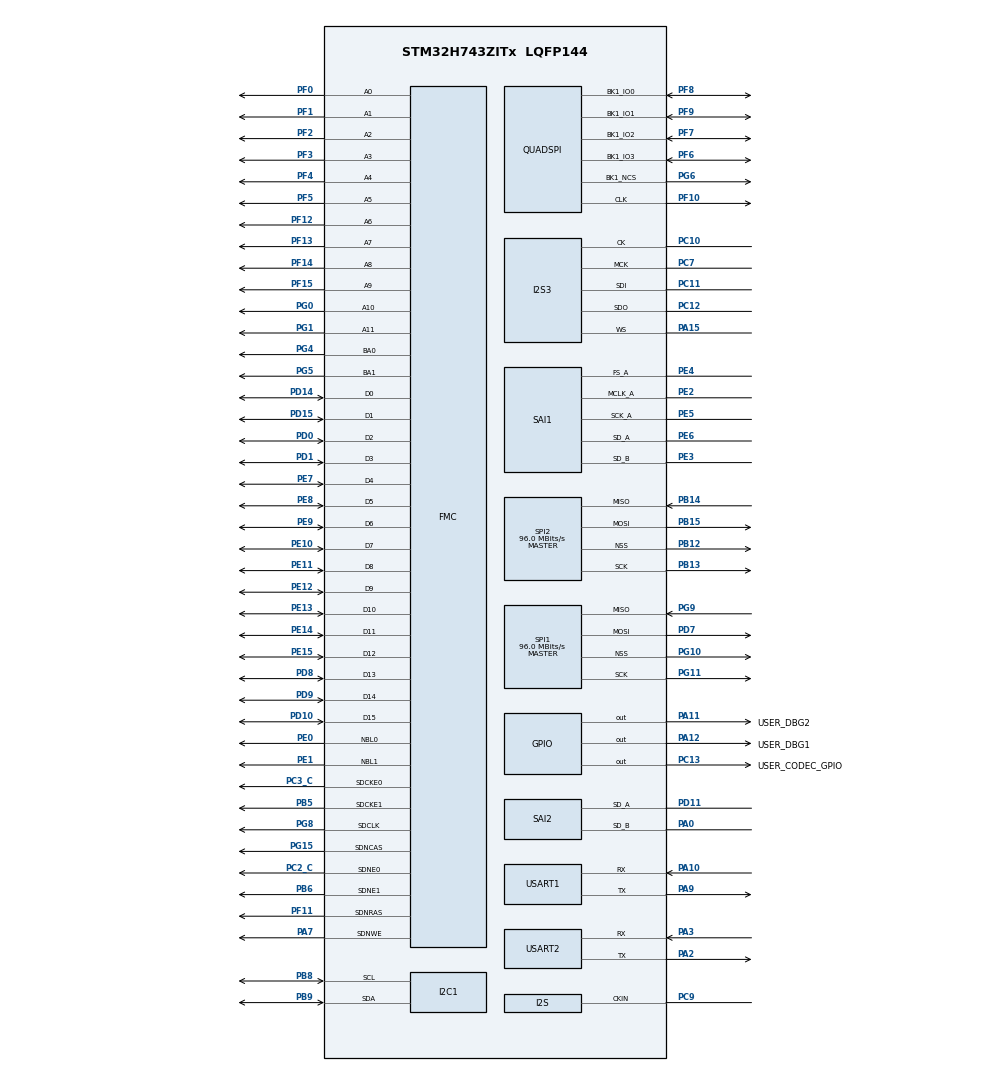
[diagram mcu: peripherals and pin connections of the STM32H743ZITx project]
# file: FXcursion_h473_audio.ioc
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CORTEX_M7.AccessPermission-Cortex_Memory_Protection_Unit_Region0_Settings=MPU_REGION_FULL_ACCESS
CORTEX_M7.AccessPermission-Cortex_Memory_Protection_Unit_Region1_Settings=MPU_REGION_FULL_ACCESS
CORTEX_M7.AccessPermission-Cortex_Memory_Protection_Unit_Region2_Settings=MPU_REGION_FULL_ACCESS
CORTEX_M7.BaseAddress-Cortex_Memory_Protection_Unit_Region0_Settings=0x30000000
CORTEX_M7.BaseAddress-Cortex_Memory_Protection_Unit_Region1_Settings=0xC0000000
CORTEX_M7.BaseAddress-Cortex_Memory_Protection_Unit_Region2_Settings=0x38000000
CORTEX_M7.CPU_DCache=Enabled
CORTEX_M7.CPU_ICache=Enabled
CORTEX_M7.DisableExec-Cortex_Memory_Protection_Unit_Region0_Settings=MPU_INSTRUCTION_ACCESS_DISABLE
CORTEX_M7.DisableExec-Cortex_Memory_Protection_Unit_Region2_Settings=MPU_INSTRUCTION_ACCESS_DISABLE
CORTEX_M7.Enable-Cortex_Memory_Protection_Unit_Region0_Settings=MPU_REGION_ENABLE
CORTEX_M7.Enable-Cortex_Memory_Protection_Unit_Region1_Settings=MPU_REGION_ENABLE
CORTEX_M7.Enable-Cortex_Memory_Protection_Unit_Region2_Settings=MPU_REGION_ENABLE
CORTEX_M7.IsBufferable-Cortex_Memory_Protection_Unit_Region0_Settings=MPU_ACCESS_BUFFERABLE
CORTEX_M7.IsBufferable-Cortex_Memory_Protection_Unit_Region2_Settings=MPU_ACCESS_BUFFERABLE
CORTEX_M7.IsCacheable-Cortex_Memory_Protection_Unit_Region1_Settings=MPU_ACCESS_CACHEABLE
CORTEX_M7.IsShareable-Cortex_Memory_Protection_Unit_Region0_Settings=MPU_ACCESS_SHAREABLE
CORTEX_M7.IsShareable-Cortex_Memory_Protection_Unit_Region2_Settings=MPU_ACCESS_SHAREABLE
CORTEX_M7.MPU_Control=MPU_PRIVILEGED_DEFAULT
CORTEX_M7.Size-Cortex_Memory_Protection_Unit_Region0_Settings=MPU_REGION_SIZE_256KB
CORTEX_M7.Size-Cortex_Memory_Protection_Unit_Region1_Settings=MPU_REGION_SIZE_512MB
CORTEX_M7.Size-Cortex_Memory_Protection_Unit_Region2_Settings=MPU_REGION_SIZE_64KB
Dma.Request0=SAI1_A
Dma.Request1=SAI1_B
Dma.Request2=USART2_RX
Dma.Request3=USART2_TX
Dma.Request4=SPI1_RX
Dma.Request5=SPI1_TX
Dma.SAI1_A.0.Direction=DMA_PERIPH_TO_MEMORY
Dma.SAI1_A.0.EventEnable=DISABLE
Dma.SAI1_A.0.FIFOMode=DMA_FIFOMODE_DISABLE
Dma.SAI1_A.0.Instance=DMA1_Stream0
Dma.SAI1_A.0.MemDataAlignment=DMA_MDATAALIGN_WORD
Dma.SAI1_A.0.MemInc=DMA_MINC_ENABLE
Dma.SAI1_A.0.Mode=DMA_CIRCULAR
Dma.SAI1_A.0.PeriphDataAlignment=DMA_PDATAALIGN_WORD
Dma.SAI1_A.0.PeriphInc=DMA_PINC_DISABLE
Dma.SAI1_A.0.Polarity=HAL_DMAMUX_REQ_GEN_RISING
Dma.SAI1_A.0.Priority=DMA_PRIORITY_HIGH
Dma.SAI1_A.0.RequestNumber=1
Dma.SAI1_A.0.SignalID=NONE
Dma.SAI1_A.0.SyncEnable=DISABLE
Dma.SAI1_A.0.SyncPolarity=HAL_DMAMUX_SYNC_NO_EVENT
Dma.SAI1_A.0.SyncRequestNumber=1
Dma.SAI1_A.0.SyncSignalID=NONE
Dma.SAI1_B.1.Direction=DMA_MEMORY_TO_PERIPH
Dma.SAI1_B.1.EventEnable=DISABLE
Dma.SAI1_B.1.FIFOMode=DMA_FIFOMODE_DISABLE
Dma.SAI1_B.1.Instance=DMA1_Stream1
Dma.SAI1_B.1.MemDataAlignment=DMA_MDATAALIGN_WORD
Dma.SAI1_B.1.MemInc=DMA_MINC_ENABLE
Dma.SAI1_B.1.Mode=DMA_CIRCULAR
Dma.SAI1_B.1.PeriphDataAlignment=DMA_PDATAALIGN_WORD
Dma.SAI1_B.1.PeriphInc=DMA_PINC_DISABLE
Dma.SAI1_B.1.Polarity=HAL_DMAMUX_REQ_GEN_RISING
Dma.SAI1_B.1.Priority=DMA_PRIORITY_MEDIUM
Dma.SAI1_B.1.RequestNumber=1
Dma.SAI1_B.1.SignalID=NONE
Dma.SAI1_B.1.SyncEnable=DISABLE
Dma.SAI1_B.1.SyncPolarity=HAL_DMAMUX_SYNC_NO_EVENT
Dma.SAI1_B.1.SyncRequestNumber=1
Dma.SAI1_B.1.SyncSignalID=NONE
Dma.SPI1_RX.4.Direction=DMA_PERIPH_TO_MEMORY
Dma.SPI1_RX.4.EventEnable=DISABLE
Dma.SPI1_RX.4.FIFOMode=DMA_FIFOMODE_DISABLE
Dma.SPI1_RX.4.Instance=DMA1_Stream4
Dma.SPI1_RX.4.MemDataAlignment=DMA_MDATAALIGN_WORD
Dma.SPI1_RX.4.MemInc=DMA_MINC_ENABLE
Dma.SPI1_RX.4.Mode=DMA_NORMAL
Dma.SPI1_RX.4.PeriphDataAlignment=DMA_PDATAALIGN_WORD
Dma.SPI1_RX.4.PeriphInc=DMA_PINC_DISABLE
Dma.SPI1_RX.4.Polarity=HAL_DMAMUX_REQ_GEN_RISING
Dma.SPI1_RX.4.Priority=DMA_PRIORITY_LOW
Dma.SPI1_RX.4.RequestNumber=1
Dma.SPI1_RX.4.SignalID=NONE
Dma.SPI1_RX.4.SyncEnable=DISABLE
Dma.SPI1_RX.4.SyncPolarity=HAL_DMAMUX_SYNC_NO_EVENT
Dma.SPI1_RX.4.SyncRequestNumber=1
Dma.SPI1_RX.4.SyncSignalID=NONE
Dma.SPI1_TX.5.Direction=DMA_MEMORY_TO_PERIPH
Dma.SPI1_TX.5.EventEnable=DISABLE
Dma.SPI1_TX.5.FIFOMode=DMA_FIFOMODE_DISABLE
Dma.SPI1_TX.5.Instance=DMA1_Stream5
Dma.SPI1_TX.5.MemDataAlignment=DMA_MDATAALIGN_WORD
Dma.SPI1_TX.5.MemInc=DMA_MINC_ENABLE
Dma.SPI1_TX.5.Mode=DMA_NORMAL
Dma.SPI1_TX.5.PeriphDataAlignment=DMA_PDATAALIGN_WORD
Dma.SPI1_TX.5.PeriphInc=DMA_PINC_DISABLE
Dma.SPI1_TX.5.Polarity=HAL_DMAMUX_REQ_GEN_RISING
Dma.SPI1_TX.5.Priority=DMA_PRIORITY_LOW
Dma.SPI1_TX.5.RequestNumber=1
Dma.SPI1_TX.5.SignalID=NONE
Dma.SPI1_TX.5.SyncEnable=DISABLE
Dma.SPI1_TX.5.SyncPolarity=HAL_DMAMUX_SYNC_NO_EVENT
Dma.SPI1_TX.5.SyncRequestNumber=1
Dma.SPI1_TX.5.SyncSignalID=NONE
Dma.USART2_RX.2.Direction=DMA_PERIPH_TO_MEMORY
Dma.USART2_RX.2.EventEnable=DISABLE
Dma.USART2_RX.2.FIFOMode=DMA_FIFOMODE_DISABLE
Dma.USART2_RX.2.Instance=DMA1_Stream2
Dma.USART2_RX.2.MemDataAlignment=DMA_MDATAALIGN_BYTE
Dma.USART2_RX.2.MemInc=DMA_MINC_ENABLE
Dma.USART2_RX.2.Mode=DMA_CIRCULAR
Dma.USART2_RX.2.PeriphDataAlignment=DMA_PDATAALIGN_BYTE
Dma.USART2_RX.2.PeriphInc=DMA_PINC_DISABLE
Dma.USART2_RX.2.Polarity=HAL_DMAMUX_REQ_GEN_RISING
Dma.USART2_RX.2.Priority=DMA_PRIORITY_LOW
Dma.USART2_RX.2.RequestNumber=1
Dma.USART2_RX.2.SignalID=NONE
Dma.USART2_RX.2.SyncEnable=DISABLE
Dma.USART2_RX.2.SyncPolarity=HAL_DMAMUX_SYNC_NO_EVENT
Dma.USART2_RX.2.SyncRequestNumber=1
Dma.USART2_RX.2.SyncSignalID=NONE
Dma.USART2_TX.3.Direction=DMA_MEMORY_TO_PERIPH
Dma.USART2_TX.3.EventEnable=DISABLE
Dma.USART2_TX.3.FIFOMode=DMA_FIFOMODE_DISABLE
Dma.USART2_TX.3.Instance=DMA1_Stream3
Dma.USART2_TX.3.MemDataAlignment=DMA_MDATAALIGN_BYTE
Dma.USART2_TX.3.MemInc=DMA_MINC_ENABLE
Dma.USART2_TX.3.Mode=DMA_NORMAL
Dma.USART2_TX.3.PeriphDataAlignment=DMA_PDATAALIGN_BYTE
Dma.USART2_TX.3.PeriphInc=DMA_PINC_DISABLE
Dma.USART2_TX.3.Polarity=HAL_DMAMUX_REQ_GEN_RISING
Dma.USART2_TX.3.Priority=DMA_PRIORITY_LOW
Dma.USART2_TX.3.RequestNumber=1
Dma.USART2_TX.3.SignalID=NONE
Dma.USART2_TX.3.SyncEnable=DISABLE
Dma.USART2_TX.3.SyncPolarity=HAL_DMAMUX_SYNC_NO_EVENT
Dma.USART2_TX.3.SyncRequestNumber=1
Dma.USART2_TX.3.SyncSignalID=NONE
FMC.CASLatency1=FMC_SDRAM_CAS_LATENCY_2
FMC.CASLatency2=FMC_SDRAM_CAS_LATENCY_2
FMC.ColumnBitsNumber1=FMC_SDRAM_COLUMN_BITS_NUM_9
FMC.ColumnBitsNumber2=FMC_SDRAM_COLUMN_BITS_NUM_9
FMC.LoadToActiveDelay1=6
FMC.RCDDelay1=6
FMC.RPDelay1=6
FMC.RPDelay2=6
FMC.ReadBurst1=FMC_SDRAM_RBURST_ENABLE
FMC.ReadBurst2=FMC_SDRAM_RBURST_ENABLE
FMC.SDClockPeriod1=FMC_SDRAM_CLOCK_PERIOD_2
FMC.SDClockPeriod2=FMC_SDRAM_CLOCK_PERIOD_2
FMC.SelfRefreshTime1=11
FMC.WriteRecoveryTime1=6
FMC.WriteRecoveryTime2=6
I2C1.Timing=0x307075B1
I2S3.ErrorAudioFreq=0.0 %
I2S3.Instance=SPI$Index
I2S3.RealAudioFreq=48.0 KHz
Mcu.Family=STM32H7
Mcu.Name=STM32H743ZITx
Mcu.Package=LQFP144
Mcu.UserConstants=MPU_D3_NONCACHABLE_0x38__,1;FAFA,0xFAFA;CODEC_0_SAI,SAI1;CODEC_1_SAI,SAI2;CODEC_HP_I2S,SPI3;CODEC_CTRL_I2C,I2C1;SAMPLES_SPI,SPI1;FILTER_CTRL_SPI,SPI2;PSRAM_QSPI,QUADSPI;CTRL_UART,USART1;DEBUG_UART,USART2
Mdma.MDMA_Channel0.Request0=QUADSPI_FIFO_TH
Mdma.MDMA_Channel0.RequestsNb=1
Mdma.MDMA_Channel0.QUADSPI_FIFO_TH.0.BlockCount=0
Mdma.MDMA_Channel0.QUADSPI_FIFO_TH.0.BlockDataLength=0
Mdma.MDMA_Channel0.QUADSPI_FIFO_TH.0.BufferTransferLength=4
Mdma.MDMA_Channel0.QUADSPI_FIFO_TH.0.CircularMode=MDMA_LINEAR_LIST
Mdma.MDMA_Channel0.QUADSPI_FIFO_TH.0.DataAlignment=MDMA_DATAALIGN_PACKENABLE
Mdma.MDMA_Channel0.QUADSPI_FIFO_TH.0.DestBlockAddressOffset=0
Mdma.MDMA_Channel0.QUADSPI_FIFO_TH.0.DestBurst=MDMA_DEST_BURST_SINGLE
Mdma.MDMA_Channel0.QUADSPI_FIFO_TH.0.DestDataSize=MDMA_DEST_DATASIZE_BYTE
Mdma.MDMA_Channel0.QUADSPI_FIFO_TH.0.DestinationInc=MDMA_DEST_INC_BYTE
Mdma.MDMA_Channel0.QUADSPI_FIFO_TH.0.DstAddress=DST_ADDRESS
Mdma.MDMA_Channel0.QUADSPI_FIFO_TH.0.Endianness=MDMA_LITTLE_ENDIANNESS_PRESERVE
Mdma.MDMA_Channel0.QUADSPI_FIFO_TH.0.Instance=MDMA_Channel0
Mdma.MDMA_Channel0.QUADSPI_FIFO_TH.0.MaskAddress=0
Mdma.MDMA_Channel0.QUADSPI_FIFO_TH.0.MaskData=0
Mdma.MDMA_Channel0.QUADSPI_FIFO_TH.0.Priority=MDMA_PRIORITY_HIGH
Mdma.MDMA_Channel0.QUADSPI_FIFO_TH.0.Rank=First
Mdma.MDMA_Channel0.QUADSPI_FIFO_TH.0.SourceBlockAddressOffset=0
Mdma.MDMA_Channel0.QUADSPI_FIFO_TH.0.SourceBurst=MDMA_SOURCE_BURST_SINGLE
Mdma.MDMA_Channel0.QUADSPI_FIFO_TH.0.SourceDataSize=MDMA_SRC_DATASIZE_BYTE
Mdma.MDMA_Channel0.QUADSPI_FIFO_TH.0.SourceInc=MDMA_SRC_INC_BYTE
Mdma.MDMA_Channel0.QUADSPI_FIFO_TH.0.SrcAddress=SRC_ADDRESS
Mdma.MDMA_Channel0.QUADSPI_FIFO_TH.0.TransferTriggerMode=MDMA_BUFFER_TRANSFER
Mdma.RequestSet0=MDMA_Channel0
Mdma.RequestSetsNb=1
NVIC.DMA1_Stream0_IRQn=true\:0\:0\:false\:false\:true\:false\:true\:true
NVIC.DMA1_Stream1_IRQn=true\:0\:0\:false\:false\:true\:false\:true\:true
NVIC.DMA1_Stream2_IRQn=true\:0\:0\:false\:false\:true\:false\:true\:true
NVIC.DMA1_Stream3_IRQn=true\:0\:0\:false\:false\:true\:false\:true\:true
NVIC.DMA1_Stream4_IRQn=true\:0\:0\:false\:false\:true\:false\:true\:true
NVIC.DMA1_Stream5_IRQn=true\:0\:0\:false\:false\:true\:false\:true\:true
NVIC.MDMA_IRQn=true\:0\:0\:false\:false\:true\:false\:true\:true
NVIC.PriorityGroup=NVIC_PRIORITYGROUP_4
NVIC.SAI1_IRQn=true\:0\:0\:false\:false\:true\:true\:true\:true
NVIC.SPI1_IRQn=true\:0\:0\:false\:false\:true\:false\:true\:true
NVIC.USART2_IRQn=true\:0\:0\:false\:false\:true\:true\:true\:true
PA0.Mode=SAI_B_SyncSlave
PA0.Signal=SAI2_SD_B
PA10.Mode=Asynchronous
PA10.Signal=USART1_RX
PA11.GPIO_Label=USER_DBG2
PA11.Signal=GPIO_Output
PA12.GPIO_Label=USER_DBG1
PA12.GPIO_Speed=GPIO_SPEED_FREQ_VERY_HIGH
PA12.Signal=GPIO_Output
PA13\ (JTMS/SWDIO).Mode=Serial_Wire
PA13\ (JTMS/SWDIO).Signal=DEBUG_JTMS-SWDIO
PA14\ (JTCK/SWCLK).Mode=Serial_Wire
PA14\ (JTCK/SWCLK).Signal=DEBUG_JTCK-SWCLK
PA15\ (JTDI).Mode=Full_Duplex_Master
PA15\ (JTDI).Signal=I2S3_WS
PA2.Mode=Asynchronous
PA2.Signal=USART2_TX
PA3.Mode=Asynchronous
PA3.Signal=USART2_RX
PA7.Signal=FMC_SDNWE
PA9.Mode=Asynchronous
PA9.Signal=USART1_TX
PB12.Mode=NSS_Signal_Hard_Output
PB12.Signal=SPI2_NSS
PB13.Mode=Full_Duplex_Master
PB13.Signal=SPI2_SCK
PB14.Mode=Full_Duplex_Master
PB14.Signal=SPI2_MISO
PB15.Mode=Full_Duplex_Master
PB15.Signal=SPI2_MOSI
PB5.Mode=SdramChipSelect2_2
PB5.Signal=FMC_SDCKE1
PB6.Mode=SdramChipSelect2_2
PB6.Signal=FMC_SDNE1
PB8.Mode=I2C
PB8.Signal=I2C1_SCL
PB9.Mode=I2C
PB9.Signal=I2C1_SDA
PC10.Mode=Full_Duplex_Master
PC10.Signal=I2S3_CK
PC11.Mode=Full_Duplex_Master
PC11.Signal=I2S3_SDI
PC12.Mode=Full_Duplex_Master
PC12.Signal=I2S3_SDO
PC13.GPIO_Label=USER_CODEC_GPIO
PC13.Signal=GPIO_Output
PC2_C.Mode=SdramChipSelect1_1
PC2_C.Signal=FMC_SDNE0
PC3_C.Mode=SdramChipSelect1_1
PC3_C.Signal=FMC_SDCKE0
PC7.Mode=Master_Clock_Activated
PC7.Signal=I2S3_MCK
PC9.Mode=Audio_ClockIn
PC9.Signal=I2S_CKIN
PD0.Signal=FMC_D2_DA2
PD1.Signal=FMC_D3_DA3
PD10.Signal=FMC_D15_DA15
PD11.Mode=SAI_A_SyncSlave
PD11.Signal=SAI2_SD_A
PD12.Signal=SAI2_FS_A
PD13.Signal=SAI2_SCK_A
PD14.Signal=FMC_D0_DA0
PD15.Signal=FMC_D1_DA1
PD7.GPIO_Speed=GPIO_SPEED_FREQ_VERY_HIGH
PD7.Mode=Full_Duplex_Master
PD7.Signal=SPI1_MOSI
PD8.Signal=FMC_D13_DA13
PD9.Signal=FMC_D14_DA14
PE0.Signal=FMC_NBL0
PE1.Signal=FMC_NBL1
PE10.Signal=FMC_D7_DA7
PE11.Signal=FMC_D8_DA8
PE12.Signal=FMC_D9_DA9
PE13.Signal=FMC_D10_DA10
PE14.Signal=FMC_D11_DA11
PE15.Signal=FMC_D12_DA12
PE2.Mode=SAI_A_MasterWithClock
PE2.Signal=SAI1_MCLK_A
PE3.GPIO_Speed=GPIO_SPEED_FREQ_VERY_HIGH
PE3.Mode=SAI_B_SyncSlave
PE3.Signal=SAI1_SD_B
PE4.GPIO_Speed=GPIO_SPEED_FREQ_VERY_HIGH
PE4.Mode=SAI_A_MasterWithClock
PE4.Signal=SAI1_FS_A
PE5.GPIO_Speed=GPIO_SPEED_FREQ_VERY_HIGH
PE5.Mode=SAI_A_MasterWithClock
PE5.Signal=SAI1_SCK_A
PE6.GPIO_Speed=GPIO_SPEED_FREQ_VERY_HIGH
PE6.Mode=SAI_A_MasterWithClock
PE6.Signal=SAI1_SD_A
PE7.Signal=FMC_D4_DA4
PE8.Signal=FMC_D5_DA5
PE9.Signal=FMC_D6_DA6
PF0.Signal=FMC_A0
PF1.Signal=FMC_A1
PF10.Mode=Single Bank 1
PF10.Signal=QUADSPI_CLK
PF11.Signal=FMC_SDNRAS
PF12.Signal=FMC_A6
PF13.Signal=FMC_A7
PF14.Signal=FMC_A8
PF15.Signal=FMC_A9
PF2.Signal=FMC_A2
PF3.Signal=FMC_A3
PF4.Signal=FMC_A4
PF5.Signal=FMC_A5
PF6.Mode=Single Bank 1
PF6.Signal=QUADSPI_BK1_IO3
PF7.Mode=Single Bank 1
PF7.Signal=QUADSPI_BK1_IO2
PF8.Mode=Single Bank 1
PF8.Signal=QUADSPI_BK1_IO0
PF9.Mode=Single Bank 1
PF9.Signal=QUADSPI_BK1_IO1
PG0.Signal=FMC_A10
PG1.Signal=FMC_A11
PG10.GPIO_Speed=GPIO_SPEED_FREQ_VERY_HIGH
PG10.Mode=NSS_Signal_Hard_Output
PG10.Signal=SPI1_NSS
PG11.GPIO_Speed=GPIO_SPEED_FREQ_VERY_HIGH
PG11.Mode=Full_Duplex_Master
PG11.Signal=SPI1_SCK
PG15.Signal=FMC_SDNCAS
PG4.Signal=FMC_A14_BA0
PG5.Signal=FMC_A15_BA1
PG6.Mode=Single Bank 1
PG6.Signal=QUADSPI_BK1_NCS
PG8.Signal=FMC_SDCLK
PG9.GPIO_Speed=GPIO_SPEED_FREQ_VERY_HIGH
PG9.Mode=Full_Duplex_Master
PG9.Signal=SPI1_MISO
ProjectManager.HeapSize=0x200
ProjectManager.StackSize=0x400
ProjectManager.TargetToolchain=STM32CubeIDE
RCC.ADCFreq_Value=12288000
RCC.APB1Freq_Value=120000000
RCC.APB2Freq_Value=120000000
RCC.APB3Freq_Value=120000000
RCC.APB4Freq_Value=120000000
RCC.CortexFreq_Value=480000000
RCC.D1PPRE=RCC_APB3_DIV2
RCC.D2PPRE1=RCC_APB1_DIV2
RCC.D2PPRE2=RCC_APB2_DIV2
RCC.D3PPRE=RCC_APB4_DIV2
RCC.DIVM1=2
RCC.DIVM2=10
RCC.DIVM3=4
RCC.DIVN1=120
RCC.DIVN2=192
RCC.DIVN3=96
RCC.DIVP2=25
RCC.DIVQ3=8
RCC.DIVR3=4
RCC.HCLKFreq_Value=240000000
RCC.HPRE=RCC_HCLK_DIV2
RCC.HSIDiv=RCC_PLLSAIDIVR_4
RCC.PLL2FRACN=0
RCC.PLL3FRACN=0
RCC.PLLFRACN=0
RCC.SAI1CLockSelection=RCC_SAI1CLKSOURCE_PIN
RCC.SAI23CLockSelection=RCC_SAI23CLKSOURCE_PIN
RCC.SAI4ACLockSelection=RCC_SAI4ACLKSOURCE_PLL2
RCC.SAI4BCLockSelection=RCC_SAI4BCLKSOURCE_PLL2
RCC.SPI123CLockSelection=RCC_SPI123CLKSOURCE_PIN
RCC.SYSCLKFreq_VALUE=480000000
RCC.SYSCLKSource=RCC_SYSCLKSOURCE_PLLCLK
RCC.USBFreq_Value=480000000
SAI1.AudioMode-SAI_B_SyncSlave=SAI_MODESLAVE_TX
SAI1.BasicDataSize-SAI_B_SyncSlave=SAI_PROTOCOL_DATASIZE_24BIT
SAI1.BasicDataSize-SAI_A_MasterWithClock=SAI_PROTOCOL_DATASIZE_24BIT
SAI1.AudioMode-SAI_A_MasterWithClock=SAI_MODEMASTER_RX
SAI1.AudioFrequency-SAI_A_MasterWithClock=SAI_AUDIO_FREQUENCY_48K
SAI1.ErrorAudioFreq-SAI_A_MasterWithClock=-75.0 %
SAI1.InitProtocol-SAI_A_MasterWithClock=Enable
SAI1.InitProtocol-SAI_B_SyncSlave=Enable
SAI1.Instance-SAI_A_MasterWithClock=SAI$Index_Block_A
SAI1.Instance-SAI_B_SyncSlave=SAI$Index_Block_B
SAI1.MClockEnable-SAI_A_MasterWithClock=SAI_MASTERCLOCK_ENABLE
SAI1.RealAudioFreq-SAI_A_MasterWithClock=48.0 KHz
SAI1.SynchroExt=SAI_SYNCEXT_OUTBLOCKA_ENABLE
SAI1.VirtualMode-SAI_A_MasterWithClock=VM_MASTER
SAI1.VirtualMode-SAI_B_SyncSlave=VM_SLAVE
SAI1.VirtualProtocol-SAI_A_BASIC=VM_BASIC_PROTOCOL
SAI1.VirtualProtocol-SAI_B_BASIC=VM_BASIC_PROTOCOL
SAI2.Instance-SAI_A_SyncSlave=SAI$Index_Block_A
SAI2.Instance-SAI_B_SyncSlave=SAI$Index_Block_B
SAI2.VirtualMode-SAI_A_SyncSlave=VM_SLAVE
SAI2.VirtualMode-SAI_B_SyncSlave=VM_SLAVE
SH.FMC_A0.0=FMC_A0,12b-sda2
SH.FMC_A0.1=FMC_A0,12b-sda1
SH.FMC_A1.0=FMC_A1,12b-sda2
SH.FMC_A1.1=FMC_A1,12b-sda1
SH.FMC_A10.0=FMC_A10,12b-sda2
SH.FMC_A10.1=FMC_A10,12b-sda1
SH.FMC_A11.0=FMC_A11,12b-sda2
SH.FMC_A11.1=FMC_A11,12b-sda1
SH.FMC_A14_BA0.0=FMC_BA0,FourSdramBanks1
SH.FMC_A14_BA0.1=FMC_BA0,FourSdramBanks2
SH.FMC_A15_BA1.0=FMC_BA1,FourSdramBanks1
SH.FMC_A15_BA1.1=FMC_BA1,FourSdramBanks2
SH.FMC_A2.0=FMC_A2,12b-sda2
SH.FMC_A2.1=FMC_A2,12b-sda1
SH.FMC_A3.0=FMC_A3,12b-sda2
SH.FMC_A3.1=FMC_A3,12b-sda1
SH.FMC_A4.0=FMC_A4,12b-sda2
SH.FMC_A4.1=FMC_A4,12b-sda1
SH.FMC_A5.0=FMC_A5,12b-sda2
SH.FMC_A5.1=FMC_A5,12b-sda1
SH.FMC_A6.0=FMC_A6,12b-sda2
SH.FMC_A6.1=FMC_A6,12b-sda1
SH.FMC_A7.0=FMC_A7,12b-sda2
SH.FMC_A7.1=FMC_A7,12b-sda1
SH.FMC_A8.0=FMC_A8,12b-sda2
SH.FMC_A8.1=FMC_A8,12b-sda1
SH.FMC_A9.0=FMC_A9,12b-sda2
SH.FMC_A9.1=FMC_A9,12b-sda1
SH.FMC_D0_DA0.0=FMC_D0,sd-16b-d1
SH.FMC_D0_DA0.1=FMC_D0,sd-16b-d2
SH.FMC_D10_DA10.0=FMC_D10,sd-16b-d1
SH.FMC_D10_DA10.1=FMC_D10,sd-16b-d2
SH.FMC_D11_DA11.0=FMC_D11,sd-16b-d1
SH.FMC_D11_DA11.1=FMC_D11,sd-16b-d2
SH.FMC_D12_DA12.0=FMC_D12,sd-16b-d1
SH.FMC_D12_DA12.1=FMC_D12,sd-16b-d2
SH.FMC_D13_DA13.0=FMC_D13,sd-16b-d1
SH.FMC_D13_DA13.1=FMC_D13,sd-16b-d2
SH.FMC_D14_DA14.0=FMC_D14,sd-16b-d1
SH.FMC_D14_DA14.1=FMC_D14,sd-16b-d2
SH.FMC_D15_DA15.0=FMC_D15,sd-16b-d1
SH.FMC_D15_DA15.1=FMC_D15,sd-16b-d2
SH.FMC_D1_DA1.0=FMC_D1,sd-16b-d1
SH.FMC_D1_DA1.1=FMC_D1,sd-16b-d2
SH.FMC_D2_DA2.0=FMC_D2,sd-16b-d1
SH.FMC_D2_DA2.1=FMC_D2,sd-16b-d2
SH.FMC_D3_DA3.0=FMC_D3,sd-16b-d1
SH.FMC_D3_DA3.1=FMC_D3,sd-16b-d2
SH.FMC_D4_DA4.0=FMC_D4,sd-16b-d1
SH.FMC_D4_DA4.1=FMC_D4,sd-16b-d2
SH.FMC_D5_DA5.0=FMC_D5,sd-16b-d1
SH.FMC_D5_DA5.1=FMC_D5,sd-16b-d2
SH.FMC_D6_DA6.0=FMC_D6,sd-16b-d1
SH.FMC_D6_DA6.1=FMC_D6,sd-16b-d2
SH.FMC_D7_DA7.0=FMC_D7,sd-16b-d1
SH.FMC_D7_DA7.1=FMC_D7,sd-16b-d2
SH.FMC_D8_DA8.0=FMC_D8,sd-16b-d1
SH.FMC_D8_DA8.1=FMC_D8,sd-16b-d2
SH.FMC_D9_DA9.0=FMC_D9,sd-16b-d1
SH.FMC_D9_DA9.1=FMC_D9,sd-16b-d2
SH.FMC_NBL0.0=FMC_NBL0,Sd2ByteEnable1
SH.FMC_NBL0.1=FMC_NBL0,Sd2ByteEnable2
SH.FMC_NBL1.0=FMC_NBL1,Sd2ByteEnable1
SH.FMC_NBL1.1=FMC_NBL1,Sd2ByteEnable2
SH.FMC_SDCLK.0=FMC_SDCLK,12b-sda2
SH.FMC_SDCLK.1=FMC_SDCLK,12b-sda1
SH.FMC_SDNCAS.0=FMC_SDNCAS,12b-sda2
SH.FMC_SDNCAS.1=FMC_SDNCAS,12b-sda1
SH.FMC_SDNRAS.0=FMC_SDNRAS,12b-sda2
SH.FMC_SDNRAS.1=FMC_SDNRAS,12b-sda1
SH.FMC_SDNWE.0=FMC_SDNWE,12b-sda2
SH.FMC_SDNWE.1=FMC_SDNWE,12b-sda1
SPI1.BaudRatePrescaler=SPI_BAUDRATEPRESCALER_2
SPI1.CalculateBaudRate=96.0 MBits/s
SPI1.DataSize=SPI_DATASIZE_32BIT
SPI1.Direction=SPI_DIRECTION_2LINES
SPI1.Mode=SPI_MODE_MASTER
SPI1.VirtualNSS=VM_NSSHARD
SPI1.VirtualType=VM_MASTER
SPI2.CalculateBaudRate=96.0 MBits/s
SPI2.Direction=SPI_DIRECTION_2LINES
SPI2.Mode=SPI_MODE_MASTER
SPI2.VirtualNSS=VM_NSSHARD
SPI2.VirtualType=VM_MASTER
USART1.VirtualMode-Asynchronous=VM_ASYNC
USART2.RXFIFOThreshold=RXFIFO_THRESHOLD_1EIGHTHFULL
USART2.TXFIFOThreshold=TXFIFO_THRESHOLD_1EIGHTHFULL
USART2.VirtualMode-Asynchronous=VM_ASYNC
VP_SAI1_VP_$IpInstance_SAIA_SAI_BASIC.Mode=SAI_A_BASIC
VP_SAI1_VP_$IpInstance_SAIB_SAI_BASIC.Mode=SAI_B_BASIC
VP_SAI1_VP_$IpInstance_SYNCHRO_EXTERNAL.Mode=SynchroExternal
board=custom
Dma.SAI2_A.6.Direction=DMA_PERIPH_TO_MEMORY
Dma.SAI2_A.6.EventEnable=DISABLE
Dma.SAI2_A.6.FIFOMode=DMA_FIFOMODE_DISABLE
Dma.SAI2_A.6.Instance=DMA1_Stream6
Dma.SAI2_A.6.MemDataAlignment=DMA_MDATAALIGN_WORD
Dma.SAI2_A.6.MemInc=DMA_MINC_ENABLE
Dma.SAI2_A.6.Mode=DMA_CIRCULAR
Dma.SAI2_A.6.PeriphDataAlignment=DMA_PDATAALIGN_WORD
Dma.SAI2_A.6.PeriphInc=DMA_PINC_DISABLE
Dma.SAI2_A.6.Polarity=HAL_DMAMUX_REQ_GEN_RISING
Dma.SAI2_A.6.Priority=DMA_PRIORITY_HIGH
Dma.SAI2_A.6.RequestNumber=1
Dma.SAI2_A.6.SignalID=NONE
Dma.SAI2_A.6.SyncEnable=DISABLE
Dma.SAI2_A.6.SyncPolarity=HAL_DMAMUX_SYNC_NO_EVENT
Dma.SAI2_A.6.SyncRequestNumber=1
Dma.SAI2_A.6.SyncSignalID=NONE
Dma.Request6=SAI2_A
Dma.SAI2_B.7.Direction=DMA_MEMORY_TO_PERIPH
Dma.SAI2_B.7.EventEnable=DISABLE
Dma.SAI2_B.7.FIFOMode=DMA_FIFOMODE_DISABLE
Dma.SAI2_B.7.Instance=DMA1_Stream7
Dma.SAI2_B.7.MemDataAlignment=DMA_MDATAALIGN_WORD
Dma.SAI2_B.7.MemInc=DMA_MINC_ENABLE
Dma.SAI2_B.7.Mode=DMA_CIRCULAR
Dma.SAI2_B.7.PeriphDataAlignment=DMA_PDATAALIGN_WORD
Dma.SAI2_B.7.PeriphInc=DMA_PINC_DISABLE
Dma.SAI2_B.7.Polarity=HAL_DMAMUX_REQ_GEN_RISING
Dma.SAI2_B.7.Priority=DMA_PRIORITY_MEDIUM
Dma.SAI2_B.7.RequestNumber=1
Dma.SAI2_B.7.SignalID=NONE
Dma.SAI2_B.7.SyncEnable=DISABLE
Dma.SAI2_B.7.SyncPolarity=HAL_DMAMUX_SYNC_NO_EVENT
Dma.SAI2_B.7.SyncRequestNumber=1
Dma.SAI2_B.7.SyncSignalID=NONE
Dma.Request7=SAI2_B
Dma.SPI3_TX.8.Direction=DMA_MEMORY_TO_PERIPH
Dma.SPI3_TX.8.EventEnable=DISABLE
Dma.SPI3_TX.8.FIFOMode=DMA_FIFOMODE_DISABLE
Dma.SPI3_TX.8.Instance=DMA2_Stream0
Dma.SPI3_TX.8.MemDataAlignment=DMA_MDATAALIGN_WORD
Dma.SPI3_TX.8.MemInc=DMA_MINC_ENABLE
Dma.SPI3_TX.8.Mode=DMA_CIRCULAR
Dma.SPI3_TX.8.PeriphDataAlignment=DMA_PDATAALIGN_WORD
Dma.SPI3_TX.8.PeriphInc=DMA_PINC_DISABLE
Dma.SPI3_TX.8.Polarity=HAL_DMAMUX_REQ_GEN_RISING
Dma.SPI3_TX.8.Priority=DMA_PRIORITY_MEDIUM
Dma.SPI3_TX.8.RequestNumber=1
Dma.SPI3_TX.8.SignalID=NONE
Dma.SPI3_TX.8.SyncEnable=DISABLE
Dma.SPI3_TX.8.SyncPolarity=HAL_DMAMUX_SYNC_NO_EVENT
Dma.SPI3_TX.8.SyncRequestNumber=1
Dma.SPI3_TX.8.SyncSignalID=NONE
Dma.Request8=SPI3_TX
Dma.USART1_RX.9.Direction=DMA_PERIPH_TO_MEMORY
Dma.USART1_RX.9.EventEnable=DISABLE
Dma.USART1_RX.9.FIFOMode=DMA_FIFOMODE_DISABLE
Dma.USART1_RX.9.Instance=DMA2_Stream1
Dma.USART1_RX.9.MemDataAlignment=DMA_MDATAALIGN_BYTE
Dma.USART1_RX.9.MemInc=DMA_MINC_ENABLE
Dma.USART1_RX.9.Mode=DMA_CIRCULAR
Dma.USART1_RX.9.PeriphDataAlignment=DMA_PDATAALIGN_BYTE
Dma.USART1_RX.9.PeriphInc=DMA_PINC_DISABLE
Dma.USART1_RX.9.Polarity=HAL_DMAMUX_REQ_GEN_RISING
Dma.USART1_RX.9.Priority=DMA_PRIORITY_LOW
Dma.USART1_RX.9.RequestNumber=1
Dma.USART1_RX.9.SignalID=NONE
Dma.USART1_RX.9.SyncEnable=DISABLE
Dma.USART1_RX.9.SyncPolarity=HAL_DMAMUX_SYNC_NO_EVENT
Dma.USART1_RX.9.SyncRequestNumber=1
Dma.USART1_RX.9.SyncSignalID=NONE
Dma.Request9=USART1_RX
Dma.USART1_TX.10.Direction=DMA_MEMORY_TO_PERIPH
Dma.USART1_TX.10.EventEnable=DISABLE
Dma.USART1_TX.10.FIFOMode=DMA_FIFOMODE_DISABLE
Dma.USART1_TX.10.Instance=DMA2_Stream2
Dma.USART1_TX.10.MemDataAlignment=DMA_MDATAALIGN_BYTE
Dma.USART1_TX.10.MemInc=DMA_MINC_ENABLE
Dma.USART1_TX.10.Mode=DMA_NORMAL
Dma.USART1_TX.10.PeriphDataAlignment=DMA_PDATAALIGN_BYTE
Dma.USART1_TX.10.PeriphInc=DMA_PINC_DISABLE
Dma.USART1_TX.10.Polarity=HAL_DMAMUX_REQ_GEN_RISING
Dma.USART1_TX.10.Priority=DMA_PRIORITY_LOW
Dma.USART1_TX.10.RequestNumber=1
Dma.USART1_TX.10.SignalID=NONE
Dma.USART1_TX.10.SyncEnable=DISABLE
Dma.USART1_TX.10.SyncPolarity=HAL_DMAMUX_SYNC_NO_EVENT
Dma.USART1_TX.10.SyncRequestNumber=1
Dma.USART1_TX.10.SyncSignalID=NONE
Dma.Request10=USART1_TX
NVIC.USART1_IRQn=true\:0\:0\:false\:false\:true\:true\:true\:true
NVIC.SAI2_IRQn=true\:0\:0\:false\:false\:true\:true\:true\:true

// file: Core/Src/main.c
/* USER CODE BEGIN Header */
/**
  ******************************************************************************
  * @file           : main.c
  * @brief          : Main program body
  ******************************************************************************
  * @attention
  *
  * Copyright (c) 2026 STMicroelectronics.
  * All rights reserved.
  *
  * This software is licensed under terms that can be found in the LICENSE file
  * in the root directory of this software component.
  * If no LICENSE file comes with this software, it is provided AS-IS.
  *
  ******************************************************************************
  */
/* USER CODE END Header */
#include "main.h"
#include "dma.h"
#include "i2c.h"
#include "i2s.h"
#include "mdma.h"
#include "quadspi.h"
#include "sai.h"
#include "spi.h"
#include "usart.h"
#include "gpio.h"
#include "fmc.h"

/* USER CODE BEGIN Includes */

#include "audio_sys.h"
#include "audio_io.h"

#include "w9812g6jh.h"
#include "wm8731.h"

#include "ctrl_uart.h"

/* USER CODE END Includes */

void SystemClock_Config(void);
void PeriphCommonClock_Config(void);
static void MPU_Config(void);

int main(void)
{

  /* USER CODE BEGIN 1 */
  BOOLEAN bLoopMemOk;

  /* USER CODE END 1 */

  /* MPU Configuration--------------------------------------------------------*/
  MPU_Config();

  /* Enable the CPU Cache */

  /* Enable I-Cache---------------------------------------------------------*/
  SCB_EnableICache();

  /* Enable D-Cache---------------------------------------------------------*/
  SCB_EnableDCache();

  /* MCU Configuration--------------------------------------------------------*/

  /* Reset of all peripherals, Initializes the Flash interface and the Systick. */
  HAL_Init();

  /* Configure the system clock */
  SystemClock_Config();

  /* Configure the peripherals common clocks */
  PeriphCommonClock_Config();

  /* Initialize all configured peripherals */
  MX_GPIO_Init();
  MX_DMA_Init();
  MX_MDMA_Init();
  MX_FMC_Init();
  MX_SAI1_Init();
  MX_USART2_UART_Init();
  MX_SPI1_Init();
  /* No MX_QUADSPI_Init: there is no QSPI part on this board any more. Loop
   * audio moved into the two SDRAM banks - see loop_mem.h. Turn QUADSPI off in
   * the .ioc so a regeneration does not put this call back. */
  MX_I2C1_Init();
  MX_I2S3_Init();
  MX_SAI2_Init();
  MX_SPI2_Init();
  MX_USART1_UART_Init();
  /* USER CODE BEGIN 2 */

  /* ==========================================================================
   * AUDIO BRING-UP. THE ORDER HERE IS NOT COSMETIC.
   *
   * 1. Both SDRAM banks, and both BEFORE AudioSys_Init.
   *
   *    AudioSys_Init resets every effect, and those resets write into the delay
   *    lines in bank 1 and the reverb memory in bank 2. Running it against
   *    uninitialised SDRAM writes into a controller that has not been through
   *    its power-up sequence.
   *
   *    Each bank is initialised separately on purpose - see w9812g6jh.h on why
   *    a Load Mode Register command issued to both at once uses bank 1 timings.
   *
   *    Both banks now also carry a looper, so this ordering matters more than
   *    it used to: LoopMem_Init clears its windows during AudioSys_Init, and
   *    the buffers those windows read from live in these banks.
   *
   * 2. Codecs before AudioIO_Start. They are clock SLAVES: they need to be
   *    configured and out of reset before SAI1 starts driving MCLK and FS at
   *    them, or the first frames land on a device still in its default state.
   *
   * 3. AudioIO_Start absolutely last. It starts the clock, and from that moment
   *    the audio interrupt is live and the engine must already be initialised.
   * ======================================================================== */

  W9812G6JH_InitBank(&hsdram1, FMC_SDRAM_CMD_TARGET_BANK1);
  W9812G6JH_InitBank(&hsdram2, FMC_SDRAM_CMD_TARGET_BANK2);

  /* Loop audio lives in those two banks now, so prove they answer before the
   * engine starts writing takes into them. Destructive, which is why it runs
   * here and nowhere else: after this point the buffers hold real audio.
   *
   * Not fatal. Everything except the looper still works, and PROTO_DIAG carries
   * bLoopMemOk so the interface can say so rather than leaving the player to
   * discover it by pressing record. */
  bLoopMemOk = (W9812G6JH_SelfTest(SDRAM_BANK_ADDR)  == RESULT_OK) &&
               (W9812G6JH_SelfTest(SDRAM_BANK2_ADDR) == RESULT_OK);

  (void)WM8731_Init(&hi2c1, USER_CODEC_GPIO_GPIO_Port, USER_CODEC_GPIO_Pin);

  if (WM8731_Start() != RESULT_OK)
  {
    Error_Handler();
  }

  if (AudioSys_Init() != RESULT_OK)
  {
    Error_Handler();
  }

  (void)AudioIO_Init();

  if (AudioIO_Start() != RESULT_OK)
  {
    Error_Handler();
  }

  /* Last, and deliberately after the audio is already running: the interface
   * may send a configuration the instant the link comes up, and Grid_Apply has
   * to have a live engine to hand it to. */
  if (CtrlUart_Init(bLoopMemOk) != RESULT_OK)
  {
    Error_Handler();
  }

  /* USER CODE END 2 */

  /* Infinite loop */
  while (1)
  {

    /* Restarts the streams if a converter reported an error. Everything else
     * the audio path needs happens in the SAI1_A interrupt. */
    AudioIO_Service();

    /* The entire control link: drain the receiver, dispatch whatever arrived,
     * and send telemetry when it is due. None of it runs in the audio ISR. */
    CtrlUart_Service();

  }
}

void SystemClock_Config(void)
{
  RCC_OscInitTypeDef RCC_OscInitStruct = {0};
  RCC_ClkInitTypeDef RCC_ClkInitStruct = {0};

  /** Supply configuration update enable
  */
  HAL_PWREx_ConfigSupply(PWR_LDO_SUPPLY);

  /** Configure the main internal regulator output voltage
  */
  __HAL_PWR_VOLTAGESCALING_CONFIG(PWR_REGULATOR_VOLTAGE_SCALE0);

  while(!__HAL_PWR_GET_FLAG(PWR_FLAG_VOSRDY)) {}

  /** Initializes the RCC Oscillators according to the specified parameters
  * in the RCC_OscInitTypeDef structure.
  */
  /* --------------------------------------------------------------------------
   * CORE CLOCK SOURCE - HSI, deliberately.
   *
   * There is no HSE on this board: PH0/PH1 are unconnected and the only
   * oscillator, Y1 (24.576 MHz), goes to I2S_CKIN for the audio path.
   *
   * HSI is +/-1%, which affects the core clock, UART baud (inside budget at
   * 115200) and cycle-based timing. It does NOT affect audio: every audio clock
   * comes from the crystal - see PeriphCommonClock_Config.
   * ------------------------------------------------------------------------ */
  RCC_OscInitStruct.OscillatorType = RCC_OSCILLATORTYPE_HSI;
  RCC_OscInitStruct.HSIState = RCC_HSI_DIV4;
  RCC_OscInitStruct.HSICalibrationValue = RCC_HSICALIBRATION_DEFAULT;
  RCC_OscInitStruct.PLL.PLLState = RCC_PLL_ON;
  RCC_OscInitStruct.PLL.PLLSource = RCC_PLLSOURCE_HSI;
  RCC_OscInitStruct.PLL.PLLM = 2;
  RCC_OscInitStruct.PLL.PLLN = 120;
  RCC_OscInitStruct.PLL.PLLP = 2;
  RCC_OscInitStruct.PLL.PLLQ = 2;
  RCC_OscInitStruct.PLL.PLLR = 2;
  RCC_OscInitStruct.PLL.PLLRGE = RCC_PLL1VCIRANGE_3;
  RCC_OscInitStruct.PLL.PLLVCOSEL = RCC_PLL1VCOWIDE;
  RCC_OscInitStruct.PLL.PLLFRACN = 0;
  if (HAL_RCC_OscConfig(&RCC_OscInitStruct) != HAL_OK)
  {
    Error_Handler();
  }

  /** Initializes the CPU, AHB and APB buses clocks
  */
  RCC_ClkInitStruct.ClockType = RCC_CLOCKTYPE_HCLK|RCC_CLOCKTYPE_SYSCLK
                              |RCC_CLOCKTYPE_PCLK1|RCC_CLOCKTYPE_PCLK2
                              |RCC_CLOCKTYPE_D3PCLK1|RCC_CLOCKTYPE_D1PCLK1;
  RCC_ClkInitStruct.SYSCLKSource = RCC_SYSCLKSOURCE_PLLCLK;
  RCC_ClkInitStruct.SYSCLKDivider = RCC_SYSCLK_DIV1;
  RCC_ClkInitStruct.AHBCLKDivider = RCC_HCLK_DIV2;
  RCC_ClkInitStruct.APB3CLKDivider = RCC_APB3_DIV2;
  RCC_ClkInitStruct.APB1CLKDivider = RCC_APB1_DIV2;
  RCC_ClkInitStruct.APB2CLKDivider = RCC_APB2_DIV2;
  RCC_ClkInitStruct.APB4CLKDivider = RCC_APB4_DIV2;

  if (HAL_RCC_ClockConfig(&RCC_ClkInitStruct, FLASH_LATENCY_4) != HAL_OK)
  {
    Error_Handler();
  }
}

void PeriphCommonClock_Config(void)
{
  RCC_PeriphCLKInitTypeDef PeriphClkInitStruct = {0};

  /** Initializes the peripherals clock
  */
  /* --------------------------------------------------------------------------
   * EVERY AUDIO CLOCK COMES FROM THE 24.576 MHz CRYSTAL (Y1 -> I2S_CKIN, PC9).
   *
   * This is not a preference, it is required. The MCU has no HSE on this board,
   * so the PLLs run from HSI, which is +/-1% and drifts with temperature. A SAI
   * clocked from an HSI-derived PLL would be 48 kHz +/-480 ppm and would slide
   * against the two codecs that ARE on the crystal - audible drift, then
   * periodic glitches.
   *
   * 24.576 MHz = 512 x 48 kHz, so every divider below is exact:
   *     MCLK  = 24.576 / 2  = 12.288 MHz  = 256 x Fs   (what the WM8731 wants)
   *     BCLK  = 64 x Fs     =  3.072 MHz               (2 slots x 32-bit)
   *
   * SPI123 NO LONGER NEEDS THE CRYSTAL.
   *
   * SPI1, SPI2 and SPI3/I2S3 share one kernel selection (D2CCIP1R.SPI123SEL),
   * and this note used to read "I2S3 must have the crystal, so SPI1 gets it
   * too" - capping the board-to-board link at 24.576/2 = 12.288 Mbit/s, half of
   * which the recorder stream alone consumes.
   *
   * I2S3 is now a SLAVE, taking CK and WS from SAI1 block A (see i2s.c). It
   * derives nothing from the kernel, so the whole SPI123 domain is free to run
   * from a PLL, and SPI1 can carry loop transport alongside the recorder.
   *
   * The audio path is unaffected: SAI1 and SAI23 keep _PIN, so every sample
   * clock in the system still comes from Y1. The headphone codec is now on the
   * same clock EDGE as the other two rather than merely the same frequency.
   *
   * PLL3P is 192 MHz so SPI1's minimum /2 prescaler lands exactly on 96 MHz -
   * see spi_tp_cfg.h for why 96 and not 48.
   *
   *     HSI 64 MHz / PLL3M 8 = 8 MHz  x PLL3N 96 = 768 MHz VCO  / PLL3P 4
   *
   * HSI-derived is fine HERE and nowhere else on this board: the SPI link is
   * synchronous - the slave samples the clock it is given - so the +/-1% of an
   * untrimmed HSI costs a little throughput and nothing else. It would still be
   * unacceptable for anything that has to stay in step with the converters.
   * ------------------------------------------------------------------------ */
  PeriphClkInitStruct.PeriphClockSelection = RCC_PERIPHCLK_SAI1|RCC_PERIPHCLK_SAI2
                              |RCC_PERIPHCLK_SPI3|RCC_PERIPHCLK_SPI2
                              |RCC_PERIPHCLK_SPI1;
  PeriphClkInitStruct.PLL3.PLL3M = 8;
  PeriphClkInitStruct.PLL3.PLL3N = 96;
  PeriphClkInitStruct.PLL3.PLL3P = 4;
  PeriphClkInitStruct.PLL3.PLL3Q = 4;
  PeriphClkInitStruct.PLL3.PLL3R = 2;
  PeriphClkInitStruct.PLL3.PLL3RGE = RCC_PLL3VCIRANGE_3;
  PeriphClkInitStruct.PLL3.PLL3VCOSEL = RCC_PLL3VCOWIDE;
  PeriphClkInitStruct.PLL3.PLL3FRACN = 0;
  PeriphClkInitStruct.Sai1ClockSelection  = RCC_SAI1CLKSOURCE_PIN;
  PeriphClkInitStruct.Sai23ClockSelection = RCC_SAI23CLKSOURCE_PIN;
  PeriphClkInitStruct.Spi123ClockSelection = RCC_SPI123CLKSOURCE_PLL3;

  if (HAL_RCCEx_PeriphCLKConfig(&PeriphClkInitStruct) != HAL_OK)
  {
    Error_Handler();
  }
}

 /* MPU Configuration */

void MPU_Config(void)
{
  MPU_Region_InitTypeDef MPU_InitStruct = {0};

  /* Disables the MPU */
  HAL_MPU_Disable();

  /* ==========================================================================
   * Region 0 - RAM_D2, the audio DMA buffers. NON-CACHEABLE.
   *
   * As generated this region covered 8 KiB at 0x24000000, which was wrong twice
   * over: nothing DMA related was placed there, and the 8 KiB window landed in
   * the middle of the modulation delay lines, leaving part of them cacheable
   * and part not.
   *
   * The audio buffers live in RAM_D2 because DMA1 and DMA2 are D2 masters and
   * cannot reach the TCMs at all. Nothing else is placed in RAM_D2, so the
   * whole region can be marked non-cacheable and no cache maintenance is needed
   * around any transfer.
   * ======================================================================== */
  MPU_InitStruct.Enable = MPU_REGION_ENABLE;
  MPU_InitStruct.Number = MPU_REGION_NUMBER0;
  MPU_InitStruct.BaseAddress = 0x30000000;
  MPU_InitStruct.Size = MPU_REGION_SIZE_256KB;
  MPU_InitStruct.SubRegionDisable = 0x0;
  MPU_InitStruct.TypeExtField = MPU_TEX_LEVEL0;
  MPU_InitStruct.AccessPermission = MPU_REGION_FULL_ACCESS;
  MPU_InitStruct.DisableExec = MPU_INSTRUCTION_ACCESS_DISABLE;
  MPU_InitStruct.IsShareable = MPU_ACCESS_SHAREABLE;
  MPU_InitStruct.IsCacheable = MPU_ACCESS_NOT_CACHEABLE;
  MPU_InitStruct.IsBufferable = MPU_ACCESS_BUFFERABLE;

  HAL_MPU_ConfigRegion(&MPU_InitStruct);

  /* ==========================================================================
   * Region 1 - BOTH SDRAM banks. Write-through, no write allocate.
   *
   * 512 MiB, not the generated 256 MiB. 256 MiB reaches 0xCFFFFFFF and stops,
   * which covers the delay lines in bank 1 and leaves the reverb in bank 2 at
   * 0xD0000000 on the default write-back write-allocate mapping - a different
   * cache policy for the two halves of the same design, by accident.
   *
   * Write-through with no write allocate is deliberate: delay and reverb lines
   * are streamed with almost no reuse, so write-allocate would buy a
   * read-for-ownership on data that is never read back.
   * ======================================================================== */
  MPU_InitStruct.Number = MPU_REGION_NUMBER1;
  MPU_InitStruct.BaseAddress = 0xC0000000;
  MPU_InitStruct.Size = MPU_REGION_SIZE_512MB;
  MPU_InitStruct.DisableExec = MPU_INSTRUCTION_ACCESS_ENABLE;
  MPU_InitStruct.IsShareable = MPU_ACCESS_NOT_SHAREABLE;
  MPU_InitStruct.IsCacheable = MPU_ACCESS_CACHEABLE;
  MPU_InitStruct.IsBufferable = MPU_ACCESS_NOT_BUFFERABLE;

  HAL_MPU_ConfigRegion(&MPU_InitStruct);

  /** Initializes and configures the Region and the memory to be protected
  */
  MPU_InitStruct.Number = MPU_REGION_NUMBER2;
  MPU_InitStruct.BaseAddress = 0x38000000;
  MPU_InitStruct.Size = MPU_REGION_SIZE_64KB;
  MPU_InitStruct.DisableExec = MPU_INSTRUCTION_ACCESS_DISABLE;
  MPU_InitStruct.IsShareable = MPU_ACCESS_SHAREABLE;
  MPU_InitStruct.IsCacheable = MPU_ACCESS_NOT_CACHEABLE;
  MPU_InitStruct.IsBufferable = MPU_ACCESS_BUFFERABLE;

  HAL_MPU_ConfigRegion(&MPU_InitStruct);
  /* Enables the MPU */
  HAL_MPU_Enable(MPU_PRIVILEGED_DEFAULT);

}

void Error_Handler(void)
{
  __disable_irq();
  while (1)
  {
  }
}
